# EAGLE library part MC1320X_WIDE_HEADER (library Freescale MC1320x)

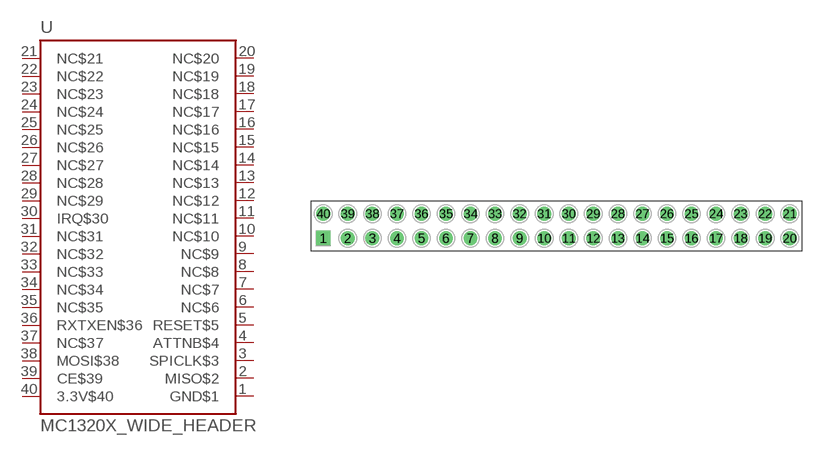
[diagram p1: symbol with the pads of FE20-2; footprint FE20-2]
Designator prefix -

## MC1320X_WIDE_HEADER  [FE20-2]
1  GND$1
2  MISO$2
3  SPICLK$3
4  ATTNB$4
5  RESET$5
6  NC$6
7  NC$7
8  NC$8
9  NC$9
10  NC$10
11  NC$11
12  NC$12
13  NC$13
14  NC$14
15  NC$15
16  NC$16
17  NC$17
18  NC$18
19  NC$19
20  NC$20
21  NC$21
22  NC$22
23  NC$23
24  NC$24
25  NC$25
26  NC$26
27  NC$27
28  NC$28
29  NC$29
30  IRQ$30
31  NC$31
32  NC$32
33  NC$33
34  NC$34
35  NC$35
36  RXTXEN$36
37  NC$37
38  MOSI$38
39  CE$39
40  3.3V$40

## Footprint FE20-2 (pad centres in mm)
drill 0.914 square: 1 -24.13,-1.27
drill 0.914: 2 -21.59,-1.27; 3 -19.05,-1.27; 4 -16.51,-1.27; 5 -13.97,-1.27; 6 -11.43,-1.27; 7 -8.89,-1.27; 8 -6.35,-1.27; 9 -3.81,-1.27; 10 -1.27,-1.27; 11 1.27,-1.27; 12 3.81,-1.27; 13 6.35,-1.27; 14 8.89,-1.27; 15 11.43,-1.27; 16 13.97,-1.27; 17 16.51,-1.27; 18 19.05,-1.27; 19 21.59,-1.27; 20 24.13,-1.27; 21 24.13,1.27; 22 21.59,1.27; 23 19.05,1.27; 24 16.51,1.27; 25 13.97,1.27; 26 11.43,1.27; 27 8.89,1.27; 28 6.35,1.27; 29 3.81,1.27; 30 1.27,1.27; 31 -1.27,1.27; 32 -3.81,1.27; 33 -6.35,1.27; 34 -8.89,1.27; 35 -11.43,1.27; 36 -13.97,1.27; 37 -16.51,1.27; 38 -19.05,1.27; 39 -21.59,1.27; 40 -24.13,1.27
